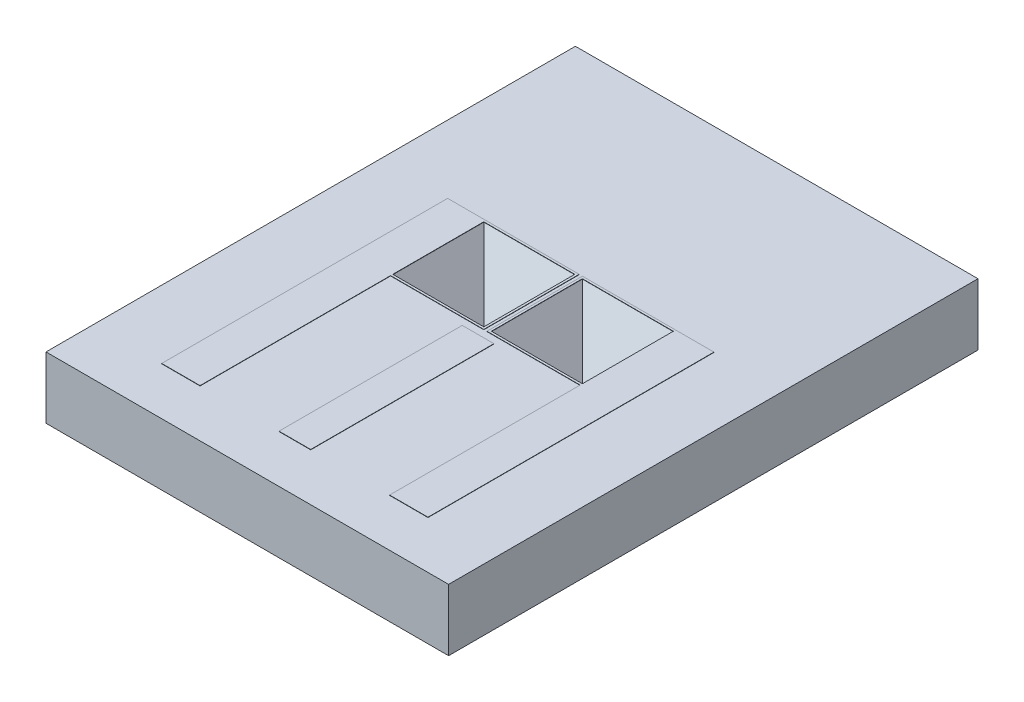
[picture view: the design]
ISO-10303-21;
HEADER;
FILE_DESCRIPTION(('STEP AP214'),'2;1');
FILE_NAME('part.step','',(''),(''),'','','');
FILE_SCHEMA(('AUTOMOTIVE_DESIGN { 1 0 10303 214 1 1 1 1 }'));
ENDSEC;
DATA;
#1=APPLICATION_CONTEXT('core data for automotive mechanical design processes');
#2=APPLICATION_PROTOCOL_DEFINITION('international standard','automotive_design',2000,#1);
#3=PRODUCT_CONTEXT('',#1,'mechanical');
#4=PRODUCT('Part','Part','',(#3));
#5=PRODUCT_RELATED_PRODUCT_CATEGORY('part','',(#4));
#6=PRODUCT_DEFINITION_FORMATION('','',#4);
#7=PRODUCT_DEFINITION_CONTEXT('part definition',#1,'design');
#8=PRODUCT_DEFINITION('design','',#6,#7);
#9=PRODUCT_DEFINITION_SHAPE('','',#8);
#10=(LENGTH_UNIT() NAMED_UNIT(*) SI_UNIT(.MILLI.,.METRE.));
#11=(NAMED_UNIT(*) PLANE_ANGLE_UNIT() SI_UNIT($,.RADIAN.));
#12=(NAMED_UNIT(*) SI_UNIT($,.STERADIAN.) SOLID_ANGLE_UNIT());
#13=UNCERTAINTY_MEASURE_WITH_UNIT(LENGTH_MEASURE(1.E-05),#10,'distance_accuracy_value','');
#14=(GEOMETRIC_REPRESENTATION_CONTEXT(3) GLOBAL_UNCERTAINTY_ASSIGNED_CONTEXT((#13)) GLOBAL_UNIT_ASSIGNED_CONTEXT((#10,
#11,#12)) REPRESENTATION_CONTEXT('',''));
#15=CARTESIAN_POINT('',(0.,0.,0.));
#16=DIRECTION('',(0.,0.,1.));
#17=DIRECTION('',(1.,0.,0.));
#18=AXIS2_PLACEMENT_3D('',#15,#16,#17);
#19=CARTESIAN_POINT('',(-1.6129,-0.4953,4.2418));
#20=DIRECTION('',(0.,1.,0.));
#21=DIRECTION('',(0.,0.,1.));
#22=AXIS2_PLACEMENT_3D('',#19,#20,#21);
#23=PLANE('',#22);
#24=DIRECTION('',(0.,0.,1.));
#25=VECTOR('',#24,1.);
#26=CARTESIAN_POINT('',(-1.6129,-0.4953,0.));
#27=LINE('',#26,#25);
#28=CARTESIAN_POINT('',(-1.6129,-0.4953,0.));
#29=VERTEX_POINT('',#28);
#30=CARTESIAN_POINT('',(-1.6129,-0.4953,4.2418));
#31=VERTEX_POINT('',#30);
#32=EDGE_CURVE('E484',#29,#31,#27,.T.);
#33=ORIENTED_EDGE('',*,*,#32,.F.);
#34=DIRECTION('',(-1.,0.,0.));
#35=VECTOR('',#34,1.);
#36=CARTESIAN_POINT('',(-1.6129,-0.4953,0.));
#37=LINE('',#36,#35);
#38=CARTESIAN_POINT('',(1.6129,-0.4953,0.));
#39=VERTEX_POINT('',#38);
#40=EDGE_CURVE('E494',#39,#29,#37,.T.);
#41=ORIENTED_EDGE('',*,*,#40,.F.);
#42=DIRECTION('',(0.,0.,-1.));
#43=VECTOR('',#42,1.);
#44=CARTESIAN_POINT('',(1.6129,-0.4953,0.));
#45=LINE('',#44,#43);
#46=CARTESIAN_POINT('',(1.6129,-0.4953,4.2418));
#47=VERTEX_POINT('',#46);
#48=EDGE_CURVE('E491',#47,#39,#45,.T.);
#49=ORIENTED_EDGE('',*,*,#48,.F.);
#50=DIRECTION('',(1.,0.,0.));
#51=VECTOR('',#50,1.);
#52=CARTESIAN_POINT('',(-1.6129,-0.4953,4.2418));
#53=LINE('',#52,#51);
#54=EDGE_CURVE('E487',#31,#47,#53,.T.);
#55=ORIENTED_EDGE('',*,*,#54,.F.);
#56=EDGE_LOOP('',(#33,#41,#49,#55));
#57=FACE_BOUND('',#56,.T.);
#58=CARTESIAN_POINT('',(0.,-0.4953,2.1209));
#59=DIRECTION('',(0.,1.,0.));
#60=DIRECTION('',(0.,0.,1.));
#61=AXIS2_PLACEMENT_3D('',#58,#59,#60);
#62=CIRCLE('',#61,0.79375);
#63=CARTESIAN_POINT('',(0.,-0.4953,2.91465));
#64=VERTEX_POINT('',#63);
#65=EDGE_CURVE('E11',#64,#64,#62,.F.);
#66=ORIENTED_EDGE('',*,*,#65,.F.);
#67=EDGE_LOOP('',(#66));
#68=FACE_BOUND('',#67,.T.);
#69=ADVANCED_FACE('F34',(#57,#68),#23,.F.);
#70=CARTESIAN_POINT('',(-1.6129,0.,4.2418));
#71=DIRECTION('',(0.,1.,0.));
#72=DIRECTION('',(0.,0.,1.));
#73=AXIS2_PLACEMENT_3D('',#70,#71,#72);
#74=PLANE('',#73);
#75=DIRECTION('',(0.,0.,1.));
#76=VECTOR('',#75,1.);
#77=CARTESIAN_POINT('',(0.127,0.,2.39268));
#78=LINE('',#77,#76);
#79=CARTESIAN_POINT('',(0.127,0.,2.39268));
#80=VERTEX_POINT('',#79);
#81=CARTESIAN_POINT('',(0.127,0.,3.8608));
#82=VERTEX_POINT('',#81);
#83=EDGE_CURVE('E267',#80,#82,#78,.T.);
#84=ORIENTED_EDGE('',*,*,#83,.T.);
#85=DIRECTION('',(1.,0.,0.));
#86=VECTOR('',#85,1.);
#87=CARTESIAN_POINT('',(0.,0.,3.8608));
#88=LINE('',#87,#86);
#89=CARTESIAN_POINT('',(-0.127,0.,3.8608));
#90=VERTEX_POINT('',#89);
#91=EDGE_CURVE('E257',#90,#82,#88,.T.);
#92=ORIENTED_EDGE('',*,*,#91,.F.);
#93=DIRECTION('',(0.,0.,1.));
#94=VECTOR('',#93,1.);
#95=CARTESIAN_POINT('',(-0.127,0.,2.39268));
#96=LINE('',#95,#94);
#97=CARTESIAN_POINT('',(-0.127,0.,2.39268));
#98=VERTEX_POINT('',#97);
#99=EDGE_CURVE('E376',#98,#90,#96,.T.);
#100=ORIENTED_EDGE('',*,*,#99,.F.);
#101=DIRECTION('',(-1.,0.,0.));
#102=VECTOR('',#101,1.);
#103=CARTESIAN_POINT('',(0.,0.,2.39268));
#104=LINE('',#103,#102);
#105=EDGE_CURVE('E357',#80,#98,#104,.T.);
#106=ORIENTED_EDGE('',*,*,#105,.F.);
#107=EDGE_LOOP('',(#84,#92,#100,#106));
#108=FACE_BOUND('',#107,.T.);
#109=DIRECTION('',(0.,0.,1.));
#110=VECTOR('',#109,1.);
#111=CARTESIAN_POINT('',(1.0668,0.,3.8608));
#112=LINE('',#111,#110);
#113=CARTESIAN_POINT('',(1.0668,0.,1.56972));
#114=VERTEX_POINT('',#113);
#115=CARTESIAN_POINT('',(1.0668,0.,3.8608));
#116=VERTEX_POINT('',#115);
#117=EDGE_CURVE('E297',#114,#116,#112,.T.);
#118=ORIENTED_EDGE('',*,*,#117,.T.);
#119=DIRECTION('',(-1.,0.,0.));
#120=VECTOR('',#119,1.);
#121=CARTESIAN_POINT('',(1.0668,0.,3.8608));
#122=LINE('',#121,#120);
#123=CARTESIAN_POINT('',(0.75946,0.,3.8608));
#124=VERTEX_POINT('',#123);
#125=EDGE_CURVE('E302',#116,#124,#122,.T.);
#126=ORIENTED_EDGE('',*,*,#125,.T.);
#127=DIRECTION('',(0.,0.,-1.));
#128=VECTOR('',#127,1.);
#129=CARTESIAN_POINT('',(0.759459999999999,0.,3.8608));
#130=LINE('',#129,#128);
#131=CARTESIAN_POINT('',(0.759459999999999,0.,2.33426));
#132=VERTEX_POINT('',#131);
#133=EDGE_CURVE('E323',#124,#132,#130,.T.);
#134=ORIENTED_EDGE('',*,*,#133,.T.);
#135=DIRECTION('',(-1.,0.,0.));
#136=VECTOR('',#135,1.);
#137=CARTESIAN_POINT('',(0.759459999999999,0.,2.33426));
#138=LINE('',#137,#136);
#139=CARTESIAN_POINT('',(0.0126999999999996,0.,2.33426));
#140=VERTEX_POINT('',#139);
#141=EDGE_CURVE('E321',#132,#140,#138,.T.);
#142=ORIENTED_EDGE('',*,*,#141,.T.);
#143=DIRECTION('',(0.,0.,-1.));
#144=VECTOR('',#143,1.);
#145=CARTESIAN_POINT('',(0.0126999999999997,0.,2.33426));
#146=LINE('',#145,#144);
#147=CARTESIAN_POINT('',(0.0126999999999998,0.,1.56972));
#148=VERTEX_POINT('',#147);
#149=EDGE_CURVE('E54',#140,#148,#146,.T.);
#150=ORIENTED_EDGE('',*,*,#149,.T.);
#151=DIRECTION('',(1.,0.,0.));
#152=VECTOR('',#151,1.);
#153=CARTESIAN_POINT('',(1.0668,0.,1.56972));
#154=LINE('',#153,#152);
#155=EDGE_CURVE('E49',#148,#114,#154,.T.);
#156=ORIENTED_EDGE('',*,*,#155,.T.);
#157=EDGE_LOOP('',(#118,#126,#134,#142,#150,#156));
#158=FACE_BOUND('',#157,.T.);
#159=DIRECTION('',(0.,0.,1.));
#160=VECTOR('',#159,1.);
#161=CARTESIAN_POINT('',(-1.6129,0.,0.));
#162=LINE('',#161,#160);
#163=CARTESIAN_POINT('',(-1.6129,0.,0.));
#164=VERTEX_POINT('',#163);
#165=CARTESIAN_POINT('',(-1.6129,0.,4.2418));
#166=VERTEX_POINT('',#165);
#167=EDGE_CURVE('E463',#164,#166,#162,.T.);
#168=ORIENTED_EDGE('',*,*,#167,.T.);
#169=DIRECTION('',(1.,0.,0.));
#170=VECTOR('',#169,1.);
#171=CARTESIAN_POINT('',(-1.6129,0.,4.2418));
#172=LINE('',#171,#170);
#173=CARTESIAN_POINT('',(1.6129,0.,4.2418));
#174=VERTEX_POINT('',#173);
#175=EDGE_CURVE('E500',#166,#174,#172,.T.);
#176=ORIENTED_EDGE('',*,*,#175,.T.);
#177=DIRECTION('',(0.,0.,-1.));
#178=VECTOR('',#177,1.);
#179=CARTESIAN_POINT('',(1.6129,0.,0.));
#180=LINE('',#179,#178);
#181=CARTESIAN_POINT('',(1.6129,0.,0.));
#182=VERTEX_POINT('',#181);
#183=EDGE_CURVE('E503',#174,#182,#180,.T.);
#184=ORIENTED_EDGE('',*,*,#183,.T.);
#185=DIRECTION('',(-1.,0.,0.));
#186=VECTOR('',#185,1.);
#187=CARTESIAN_POINT('',(-1.6129,0.,0.));
#188=LINE('',#187,#186);
#189=EDGE_CURVE('E488',#182,#164,#188,.T.);
#190=ORIENTED_EDGE('',*,*,#189,.T.);
#191=EDGE_LOOP('',(#168,#176,#184,#190));
#192=FACE_BOUND('',#191,.T.);
#193=DIRECTION('',(1.,0.,0.));
#194=VECTOR('',#193,1.);
#195=CARTESIAN_POINT('',(-1.0668,0.,3.8608));
#196=LINE('',#195,#194);
#197=CARTESIAN_POINT('',(-1.0668,0.,3.8608));
#198=VERTEX_POINT('',#197);
#199=CARTESIAN_POINT('',(-0.759459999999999,0.,3.8608));
#200=VERTEX_POINT('',#199);
#201=EDGE_CURVE('E422',#198,#200,#196,.T.);
#202=ORIENTED_EDGE('',*,*,#201,.F.);
#203=DIRECTION('',(0.,0.,1.));
#204=VECTOR('',#203,1.);
#205=CARTESIAN_POINT('',(-1.0668,0.,3.8608));
#206=LINE('',#205,#204);
#207=CARTESIAN_POINT('',(-1.0668,0.,1.56972));
#208=VERTEX_POINT('',#207);
#209=EDGE_CURVE('E404',#208,#198,#206,.T.);
#210=ORIENTED_EDGE('',*,*,#209,.F.);
#211=DIRECTION('',(-1.,0.,0.));
#212=VECTOR('',#211,1.);
#213=CARTESIAN_POINT('',(-1.0668,0.,1.56972));
#214=LINE('',#213,#212);
#215=CARTESIAN_POINT('',(-0.0126999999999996,0.,1.56972));
#216=VERTEX_POINT('',#215);
#217=EDGE_CURVE('E409',#216,#208,#214,.T.);
#218=ORIENTED_EDGE('',*,*,#217,.F.);
#219=DIRECTION('',(0.,0.,-1.));
#220=VECTOR('',#219,1.);
#221=CARTESIAN_POINT('',(-0.0126999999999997,0.,2.33426));
#222=LINE('',#221,#220);
#223=CARTESIAN_POINT('',(-0.0126999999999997,0.,2.33426));
#224=VERTEX_POINT('',#223);
#225=EDGE_CURVE('E428',#224,#216,#222,.T.);
#226=ORIENTED_EDGE('',*,*,#225,.F.);
#227=DIRECTION('',(1.,0.,0.));
#228=VECTOR('',#227,1.);
#229=CARTESIAN_POINT('',(-0.759459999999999,0.,2.33426));
#230=LINE('',#229,#228);
#231=CARTESIAN_POINT('',(-0.759459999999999,0.,2.33426));
#232=VERTEX_POINT('',#231);
#233=EDGE_CURVE('E426',#232,#224,#230,.T.);
#234=ORIENTED_EDGE('',*,*,#233,.F.);
#235=DIRECTION('',(0.,0.,-1.));
#236=VECTOR('',#235,1.);
#237=CARTESIAN_POINT('',(-0.759459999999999,0.,3.8608));
#238=LINE('',#237,#236);
#239=EDGE_CURVE('E424',#200,#232,#238,.T.);
#240=ORIENTED_EDGE('',*,*,#239,.F.);
#241=EDGE_LOOP('',(#202,#210,#218,#226,#234,#240));
#242=FACE_BOUND('',#241,.T.);
#243=ADVANCED_FACE('F521',(#108,#158,#192,#242),#74,.T.);
#244=CARTESIAN_POINT('',(-1.6129,-0.4953,0.));
#245=DIRECTION('',(-1.,0.,0.));
#246=DIRECTION('',(0.,0.,1.));
#247=AXIS2_PLACEMENT_3D('',#244,#245,#246);
#248=PLANE('',#247);
#249=ORIENTED_EDGE('',*,*,#167,.F.);
#250=DIRECTION('',(0.,1.,0.));
#251=VECTOR('',#250,1.);
#252=CARTESIAN_POINT('',(-1.6129,-0.4953,0.));
#253=LINE('',#252,#251);
#254=EDGE_CURVE('E42',#29,#164,#253,.T.);
#255=ORIENTED_EDGE('',*,*,#254,.F.);
#256=ORIENTED_EDGE('',*,*,#32,.T.);
#257=DIRECTION('',(0.,1.,0.));
#258=VECTOR('',#257,1.);
#259=CARTESIAN_POINT('',(-1.6129,-0.4953,4.2418));
#260=LINE('',#259,#258);
#261=EDGE_CURVE('E497',#31,#166,#260,.T.);
#262=ORIENTED_EDGE('',*,*,#261,.T.);
#263=EDGE_LOOP('',(#249,#255,#256,#262));
#264=FACE_BOUND('',#263,.T.);
#265=ADVANCED_FACE('F36',(#264),#248,.T.);
#266=CARTESIAN_POINT('',(-1.6129,-0.4953,0.));
#267=DIRECTION('',(0.,0.,-1.));
#268=DIRECTION('',(-1.,0.,0.));
#269=AXIS2_PLACEMENT_3D('',#266,#267,#268);
#270=PLANE('',#269);
#271=ORIENTED_EDGE('',*,*,#189,.F.);
#272=DIRECTION('',(0.,1.,0.));
#273=VECTOR('',#272,1.);
#274=CARTESIAN_POINT('',(1.6129,-0.4953,0.));
#275=LINE('',#274,#273);
#276=EDGE_CURVE('E509',#39,#182,#275,.T.);
#277=ORIENTED_EDGE('',*,*,#276,.F.);
#278=ORIENTED_EDGE('',*,*,#40,.T.);
#279=ORIENTED_EDGE('',*,*,#254,.T.);
#280=EDGE_LOOP('',(#271,#277,#278,#279));
#281=FACE_BOUND('',#280,.T.);
#282=ADVANCED_FACE('F525',(#281),#270,.T.);
#283=CARTESIAN_POINT('',(1.6129,-0.4953,0.));
#284=DIRECTION('',(1.,0.,0.));
#285=DIRECTION('',(0.,0.,-1.));
#286=AXIS2_PLACEMENT_3D('',#283,#284,#285);
#287=PLANE('',#286);
#288=ORIENTED_EDGE('',*,*,#183,.F.);
#289=DIRECTION('',(0.,1.,0.));
#290=VECTOR('',#289,1.);
#291=CARTESIAN_POINT('',(1.6129,-0.4953,4.2418));
#292=LINE('',#291,#290);
#293=EDGE_CURVE('E511',#47,#174,#292,.T.);
#294=ORIENTED_EDGE('',*,*,#293,.F.);
#295=ORIENTED_EDGE('',*,*,#48,.T.);
#296=ORIENTED_EDGE('',*,*,#276,.T.);
#297=EDGE_LOOP('',(#288,#294,#295,#296));
#298=FACE_BOUND('',#297,.T.);
#299=ADVANCED_FACE('F531',(#298),#287,.T.);
#300=CARTESIAN_POINT('',(-1.6129,-0.4953,4.2418));
#301=DIRECTION('',(0.,0.,1.));
#302=DIRECTION('',(1.,0.,0.));
#303=AXIS2_PLACEMENT_3D('',#300,#301,#302);
#304=PLANE('',#303);
#305=ORIENTED_EDGE('',*,*,#175,.F.);
#306=ORIENTED_EDGE('',*,*,#261,.F.);
#307=ORIENTED_EDGE('',*,*,#54,.T.);
#308=ORIENTED_EDGE('',*,*,#293,.T.);
#309=EDGE_LOOP('',(#305,#306,#307,#308));
#310=FACE_BOUND('',#309,.T.);
#311=ADVANCED_FACE('F518',(#310),#304,.T.);
#312=CARTESIAN_POINT('',(-1.0668,0.00254,1.56972));
#313=DIRECTION('',(0.,-1.,0.));
#314=DIRECTION('',(0.,0.,-1.));
#315=AXIS2_PLACEMENT_3D('',#312,#313,#314);
#316=PLANE('',#315);
#317=DIRECTION('',(0.,0.,1.));
#318=VECTOR('',#317,1.);
#319=CARTESIAN_POINT('',(-1.0668,0.00254,3.8608));
#320=LINE('',#319,#318);
#321=CARTESIAN_POINT('',(-1.0668,0.00254,1.56972));
#322=VERTEX_POINT('',#321);
#323=CARTESIAN_POINT('',(-1.0668,0.00254,3.8608));
#324=VERTEX_POINT('',#323);
#325=EDGE_CURVE('E405',#322,#324,#320,.T.);
#326=ORIENTED_EDGE('',*,*,#325,.T.);
#327=DIRECTION('',(1.,0.,0.));
#328=VECTOR('',#327,1.);
#329=CARTESIAN_POINT('',(-1.0668,0.00254,3.8608));
#330=LINE('',#329,#328);
#331=CARTESIAN_POINT('',(-0.759459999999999,0.00254,3.8608));
#332=VERTEX_POINT('',#331);
#333=EDGE_CURVE('E408',#324,#332,#330,.T.);
#334=ORIENTED_EDGE('',*,*,#333,.T.);
#335=DIRECTION('',(0.,0.,-1.));
#336=VECTOR('',#335,1.);
#337=CARTESIAN_POINT('',(-0.759459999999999,0.00254,3.8608));
#338=LINE('',#337,#336);
#339=CARTESIAN_POINT('',(-0.759459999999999,0.00254,2.33426));
#340=VERTEX_POINT('',#339);
#341=EDGE_CURVE('E411',#332,#340,#338,.T.);
#342=ORIENTED_EDGE('',*,*,#341,.T.);
#343=DIRECTION('',(1.,0.,0.));
#344=VECTOR('',#343,1.);
#345=CARTESIAN_POINT('',(-0.759459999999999,0.00254,2.33426));
#346=LINE('',#345,#344);
#347=CARTESIAN_POINT('',(-0.0126999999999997,0.00254,2.33426));
#348=VERTEX_POINT('',#347);
#349=EDGE_CURVE('E413',#340,#348,#346,.T.);
#350=ORIENTED_EDGE('',*,*,#349,.T.);
#351=DIRECTION('',(0.,0.,-1.));
#352=VECTOR('',#351,1.);
#353=CARTESIAN_POINT('',(-0.0126999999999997,0.00254,2.33426));
#354=LINE('',#353,#352);
#355=CARTESIAN_POINT('',(-0.0126999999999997,0.00254,1.56972));
#356=VERTEX_POINT('',#355);
#357=EDGE_CURVE('E415',#348,#356,#354,.T.);
#358=ORIENTED_EDGE('',*,*,#357,.T.);
#359=DIRECTION('',(-1.,0.,0.));
#360=VECTOR('',#359,1.);
#361=CARTESIAN_POINT('',(-1.0668,0.00254,1.56972));
#362=LINE('',#361,#360);
#363=EDGE_CURVE('E417',#356,#322,#362,.T.);
#364=ORIENTED_EDGE('',*,*,#363,.T.);
#365=EDGE_LOOP('',(#326,#334,#342,#350,#358,#364));
#366=FACE_BOUND('',#365,.T.);
#367=DIRECTION('',(0.,0.,1.));
#368=VECTOR('',#367,1.);
#369=CARTESIAN_POINT('',(-0.75946,0.00254,1.5875));
#370=LINE('',#369,#368);
#371=CARTESIAN_POINT('',(-0.75946,0.00254,1.5875));
#372=VERTEX_POINT('',#371);
#373=CARTESIAN_POINT('',(-0.75946,0.00254,2.31648));
#374=VERTEX_POINT('',#373);
#375=EDGE_CURVE('E384',#372,#374,#370,.T.);
#376=ORIENTED_EDGE('',*,*,#375,.F.);
#377=DIRECTION('',(-1.,0.,0.));
#378=VECTOR('',#377,1.);
#379=CARTESIAN_POINT('',(-0.0304799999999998,0.00254,1.5875));
#380=LINE('',#379,#378);
#381=CARTESIAN_POINT('',(-0.0304799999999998,0.00254,1.5875));
#382=VERTEX_POINT('',#381);
#383=EDGE_CURVE('E391',#382,#372,#380,.T.);
#384=ORIENTED_EDGE('',*,*,#383,.F.);
#385=DIRECTION('',(0.,0.,-1.));
#386=VECTOR('',#385,1.);
#387=CARTESIAN_POINT('',(-0.0304799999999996,0.00254,2.31648));
#388=LINE('',#387,#386);
#389=CARTESIAN_POINT('',(-0.0304799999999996,0.00254,2.31648));
#390=VERTEX_POINT('',#389);
#391=EDGE_CURVE('E388',#390,#382,#388,.T.);
#392=ORIENTED_EDGE('',*,*,#391,.F.);
#393=DIRECTION('',(1.,0.,0.));
#394=VECTOR('',#393,1.);
#395=CARTESIAN_POINT('',(-0.75946,0.00254,2.31648));
#396=LINE('',#395,#394);
#397=EDGE_CURVE('E386',#374,#390,#396,.T.);
#398=ORIENTED_EDGE('',*,*,#397,.F.);
#399=EDGE_LOOP('',(#376,#384,#392,#398));
#400=FACE_BOUND('',#399,.T.);
#401=ADVANCED_FACE('F538',(#366,#400),#316,.F.);
#402=CARTESIAN_POINT('',(-1.0668,0.00254,3.8608));
#403=DIRECTION('',(1.,0.,0.));
#404=DIRECTION('',(0.,0.,-1.));
#405=AXIS2_PLACEMENT_3D('',#402,#403,#404);
#406=PLANE('',#405);
#407=ORIENTED_EDGE('',*,*,#209,.T.);
#408=DIRECTION('',(0.,-1.,0.));
#409=VECTOR('',#408,1.);
#410=CARTESIAN_POINT('',(-1.0668,0.00254,3.8608));
#411=LINE('',#410,#409);
#412=EDGE_CURVE('E445',#324,#198,#411,.T.);
#413=ORIENTED_EDGE('',*,*,#412,.F.);
#414=ORIENTED_EDGE('',*,*,#325,.F.);
#415=DIRECTION('',(0.,-1.,0.));
#416=VECTOR('',#415,1.);
#417=CARTESIAN_POINT('',(-1.0668,0.00254,1.56972));
#418=LINE('',#417,#416);
#419=EDGE_CURVE('E419',#322,#208,#418,.T.);
#420=ORIENTED_EDGE('',*,*,#419,.T.);
#421=EDGE_LOOP('',(#407,#413,#414,#420));
#422=FACE_BOUND('',#421,.T.);
#423=ADVANCED_FACE('F570',(#422),#406,.F.);
#424=CARTESIAN_POINT('',(-1.0668,0.00254,3.8608));
#425=DIRECTION('',(0.,0.,-1.));
#426=DIRECTION('',(-1.,0.,0.));
#427=AXIS2_PLACEMENT_3D('',#424,#425,#426);
#428=PLANE('',#427);
#429=ORIENTED_EDGE('',*,*,#201,.T.);
#430=DIRECTION('',(0.,-1.,0.));
#431=VECTOR('',#430,1.);
#432=CARTESIAN_POINT('',(-0.759459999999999,0.00254,3.8608));
#433=LINE('',#432,#431);
#434=EDGE_CURVE('E442',#332,#200,#433,.T.);
#435=ORIENTED_EDGE('',*,*,#434,.F.);
#436=ORIENTED_EDGE('',*,*,#333,.F.);
#437=ORIENTED_EDGE('',*,*,#412,.T.);
#438=EDGE_LOOP('',(#429,#435,#436,#437));
#439=FACE_BOUND('',#438,.T.);
#440=ADVANCED_FACE('F573',(#439),#428,.F.);
#441=CARTESIAN_POINT('',(-0.759459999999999,0.00254,3.8608));
#442=DIRECTION('',(-1.,0.,0.));
#443=DIRECTION('',(0.,0.,1.));
#444=AXIS2_PLACEMENT_3D('',#441,#442,#443);
#445=PLANE('',#444);
#446=ORIENTED_EDGE('',*,*,#239,.T.);
#447=DIRECTION('',(0.,-1.,0.));
#448=VECTOR('',#447,1.);
#449=CARTESIAN_POINT('',(-0.759459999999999,0.00254,2.33426));
#450=LINE('',#449,#448);
#451=EDGE_CURVE('E439',#340,#232,#450,.T.);
#452=ORIENTED_EDGE('',*,*,#451,.F.);
#453=ORIENTED_EDGE('',*,*,#341,.F.);
#454=ORIENTED_EDGE('',*,*,#434,.T.);
#455=EDGE_LOOP('',(#446,#452,#453,#454));
#456=FACE_BOUND('',#455,.T.);
#457=ADVANCED_FACE('F577',(#456),#445,.F.);
#458=CARTESIAN_POINT('',(-0.759459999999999,0.00254,2.33426));
#459=DIRECTION('',(0.,0.,-1.));
#460=DIRECTION('',(-1.,0.,0.));
#461=AXIS2_PLACEMENT_3D('',#458,#459,#460);
#462=PLANE('',#461);
#463=ORIENTED_EDGE('',*,*,#233,.T.);
#464=DIRECTION('',(0.,-1.,0.));
#465=VECTOR('',#464,1.);
#466=CARTESIAN_POINT('',(-0.0126999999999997,0.00254,2.33426));
#467=LINE('',#466,#465);
#468=EDGE_CURVE('E436',#348,#224,#467,.T.);
#469=ORIENTED_EDGE('',*,*,#468,.F.);
#470=ORIENTED_EDGE('',*,*,#349,.F.);
#471=ORIENTED_EDGE('',*,*,#451,.T.);
#472=EDGE_LOOP('',(#463,#469,#470,#471));
#473=FACE_BOUND('',#472,.T.);
#474=ADVANCED_FACE('F581',(#473),#462,.F.);
#475=CARTESIAN_POINT('',(-0.0126999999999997,0.00254,2.33426));
#476=DIRECTION('',(-1.,0.,0.));
#477=DIRECTION('',(0.,0.,1.));
#478=AXIS2_PLACEMENT_3D('',#475,#476,#477);
#479=PLANE('',#478);
#480=ORIENTED_EDGE('',*,*,#225,.T.);
#481=DIRECTION('',(0.,-1.,0.));
#482=VECTOR('',#481,1.);
#483=CARTESIAN_POINT('',(-0.0126999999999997,0.00254,1.56972));
#484=LINE('',#483,#482);
#485=EDGE_CURVE('E434',#356,#216,#484,.T.);
#486=ORIENTED_EDGE('',*,*,#485,.F.);
#487=ORIENTED_EDGE('',*,*,#357,.F.);
#488=ORIENTED_EDGE('',*,*,#468,.T.);
#489=EDGE_LOOP('',(#480,#486,#487,#488));
#490=FACE_BOUND('',#489,.T.);
#491=ADVANCED_FACE('F585',(#490),#479,.F.);
#492=CARTESIAN_POINT('',(-1.0668,0.00254,1.56972));
#493=DIRECTION('',(0.,0.,1.));
#494=DIRECTION('',(1.,0.,0.));
#495=AXIS2_PLACEMENT_3D('',#492,#493,#494);
#496=PLANE('',#495);
#497=ORIENTED_EDGE('',*,*,#217,.T.);
#498=ORIENTED_EDGE('',*,*,#419,.F.);
#499=ORIENTED_EDGE('',*,*,#363,.F.);
#500=ORIENTED_EDGE('',*,*,#485,.T.);
#501=EDGE_LOOP('',(#497,#498,#499,#500));
#502=FACE_BOUND('',#501,.T.);
#503=ADVANCED_FACE('F589',(#502),#496,.F.);
#504=CARTESIAN_POINT('',(-0.75946,0.00254,1.5875));
#505=DIRECTION('',(1.,0.,0.));
#506=DIRECTION('',(0.,0.,-1.));
#507=AXIS2_PLACEMENT_3D('',#504,#505,#506);
#508=PLANE('',#507);
#509=DIRECTION('',(0.,0.,1.));
#510=VECTOR('',#509,1.);
#511=CARTESIAN_POINT('',(-0.75946,0.,1.5875));
#512=LINE('',#511,#510);
#513=CARTESIAN_POINT('',(-0.75946,0.,1.5875));
#514=VERTEX_POINT('',#513);
#515=CARTESIAN_POINT('',(-0.75946,0.,2.31648));
#516=VERTEX_POINT('',#515);
#517=EDGE_CURVE('E447',#514,#516,#512,.T.);
#518=ORIENTED_EDGE('',*,*,#517,.F.);
#519=DIRECTION('',(0.,-1.,0.));
#520=VECTOR('',#519,1.);
#521=CARTESIAN_POINT('',(-0.75946,0.00254,1.5875));
#522=LINE('',#521,#520);
#523=EDGE_CURVE('E393',#372,#514,#522,.T.);
#524=ORIENTED_EDGE('',*,*,#523,.F.);
#525=ORIENTED_EDGE('',*,*,#375,.T.);
#526=DIRECTION('',(0.,-1.,0.));
#527=VECTOR('',#526,1.);
#528=CARTESIAN_POINT('',(-0.75946,0.00254,2.31648));
#529=LINE('',#528,#527);
#530=EDGE_CURVE('E401',#374,#516,#529,.T.);
#531=ORIENTED_EDGE('',*,*,#530,.T.);
#532=EDGE_LOOP('',(#518,#524,#525,#531));
#533=FACE_BOUND('',#532,.T.);
#534=ADVANCED_FACE('F593',(#533),#508,.T.);
#535=CARTESIAN_POINT('',(-0.75946,0.00254,2.31648));
#536=DIRECTION('',(0.,0.,-1.));
#537=DIRECTION('',(-1.,0.,0.));
#538=AXIS2_PLACEMENT_3D('',#535,#536,#537);
#539=PLANE('',#538);
#540=DIRECTION('',(1.,0.,0.));
#541=VECTOR('',#540,1.);
#542=CARTESIAN_POINT('',(-0.75946,0.,2.31648));
#543=LINE('',#542,#541);
#544=CARTESIAN_POINT('',(-0.0304799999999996,0.,2.31648));
#545=VERTEX_POINT('',#544);
#546=EDGE_CURVE('E450',#516,#545,#543,.T.);
#547=ORIENTED_EDGE('',*,*,#546,.F.);
#548=ORIENTED_EDGE('',*,*,#530,.F.);
#549=ORIENTED_EDGE('',*,*,#397,.T.);
#550=DIRECTION('',(0.,-1.,0.));
#551=VECTOR('',#550,1.);
#552=CARTESIAN_POINT('',(-0.0304799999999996,0.00254,2.31648));
#553=LINE('',#552,#551);
#554=EDGE_CURVE('E398',#390,#545,#553,.T.);
#555=ORIENTED_EDGE('',*,*,#554,.T.);
#556=EDGE_LOOP('',(#547,#548,#549,#555));
#557=FACE_BOUND('',#556,.T.);
#558=ADVANCED_FACE('F600',(#557),#539,.T.);
#559=CARTESIAN_POINT('',(-0.0304799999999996,0.00254,2.31648));
#560=DIRECTION('',(-1.,0.,0.));
#561=DIRECTION('',(0.,0.,1.));
#562=AXIS2_PLACEMENT_3D('',#559,#560,#561);
#563=PLANE('',#562);
#564=DIRECTION('',(0.,0.,-1.));
#565=VECTOR('',#564,1.);
#566=CARTESIAN_POINT('',(-0.0304799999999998,0.,1.5875));
#567=LINE('',#566,#565);
#568=CARTESIAN_POINT('',(-0.0304799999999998,0.,1.5875));
#569=VERTEX_POINT('',#568);
#570=EDGE_CURVE('E453',#545,#569,#567,.T.);
#571=ORIENTED_EDGE('',*,*,#570,.F.);
#572=ORIENTED_EDGE('',*,*,#554,.F.);
#573=ORIENTED_EDGE('',*,*,#391,.T.);
#574=DIRECTION('',(0.,-1.,0.));
#575=VECTOR('',#574,1.);
#576=CARTESIAN_POINT('',(-0.0304799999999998,0.00254,1.5875));
#577=LINE('',#576,#575);
#578=EDGE_CURVE('E396',#382,#569,#577,.T.);
#579=ORIENTED_EDGE('',*,*,#578,.T.);
#580=EDGE_LOOP('',(#571,#572,#573,#579));
#581=FACE_BOUND('',#580,.T.);
#582=ADVANCED_FACE('F604',(#581),#563,.T.);
#583=CARTESIAN_POINT('',(-0.0304799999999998,0.00254,1.5875));
#584=DIRECTION('',(0.,0.,1.));
#585=DIRECTION('',(1.,0.,0.));
#586=AXIS2_PLACEMENT_3D('',#583,#584,#585);
#587=PLANE('',#586);
#588=DIRECTION('',(-1.,0.,0.));
#589=VECTOR('',#588,1.);
#590=CARTESIAN_POINT('',(-0.75946,0.,1.5875));
#591=LINE('',#590,#589);
#592=EDGE_CURVE('E456',#569,#514,#591,.T.);
#593=ORIENTED_EDGE('',*,*,#592,.F.);
#594=ORIENTED_EDGE('',*,*,#578,.F.);
#595=ORIENTED_EDGE('',*,*,#383,.T.);
#596=ORIENTED_EDGE('',*,*,#523,.T.);
#597=EDGE_LOOP('',(#593,#594,#595,#596));
#598=FACE_BOUND('',#597,.T.);
#599=ADVANCED_FACE('F568',(#598),#587,.T.);
#600=CARTESIAN_POINT('',(-0.75946,-0.4826,2.31648));
#601=DIRECTION('',(0.,1.,0.));
#602=DIRECTION('',(0.,0.,1.));
#603=AXIS2_PLACEMENT_3D('',#600,#601,#602);
#604=PLANE('',#603);
#605=DIRECTION('',(0.,0.,1.));
#606=VECTOR('',#605,1.);
#607=CARTESIAN_POINT('',(-0.457898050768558,-0.4826,2.31648));
#608=LINE('',#607,#606);
#609=CARTESIAN_POINT('',(-0.457898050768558,-0.4826,1.88906194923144));
#610=VERTEX_POINT('',#609);
#611=CARTESIAN_POINT('',(-0.457898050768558,-0.4826,2.01491805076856));
#612=VERTEX_POINT('',#611);
#613=EDGE_CURVE('E459',#610,#612,#608,.T.);
#614=ORIENTED_EDGE('',*,*,#613,.T.);
#615=DIRECTION('',(1.,0.,0.));
#616=VECTOR('',#615,1.);
#617=CARTESIAN_POINT('',(-0.75946,-0.4826,2.01491805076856));
#618=LINE('',#617,#616);
#619=CARTESIAN_POINT('',(-0.332041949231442,-0.4826,2.01491805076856));
#620=VERTEX_POINT('',#619);
#621=EDGE_CURVE('E476',#612,#620,#618,.T.);
#622=ORIENTED_EDGE('',*,*,#621,.T.);
#623=DIRECTION('',(0.,0.,-1.));
#624=VECTOR('',#623,1.);
#625=CARTESIAN_POINT('',(-0.332041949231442,-0.4826,2.31648));
#626=LINE('',#625,#624);
#627=CARTESIAN_POINT('',(-0.332041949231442,-0.4826,1.88906194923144));
#628=VERTEX_POINT('',#627);
#629=EDGE_CURVE('E479',#620,#628,#626,.T.);
#630=ORIENTED_EDGE('',*,*,#629,.T.);
#631=DIRECTION('',(-1.,0.,0.));
#632=VECTOR('',#631,1.);
#633=CARTESIAN_POINT('',(-0.75946,-0.4826,1.88906194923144));
#634=LINE('',#633,#632);
#635=EDGE_CURVE('E469',#628,#610,#634,.T.);
#636=ORIENTED_EDGE('',*,*,#635,.T.);
#637=EDGE_LOOP('',(#614,#622,#630,#636));
#638=FACE_BOUND('',#637,.T.);
#639=ADVANCED_FACE('F560',(#638),#604,.T.);
#640=CARTESIAN_POINT('',(-0.75946,0.,2.31648));
#641=DIRECTION('',(0.,-0.529919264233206,0.848048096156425));
#642=DIRECTION('',(0.,-0.848048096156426,-0.529919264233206));
#643=AXIS2_PLACEMENT_3D('',#640,#641,#642);
#644=PLANE('',#643);
#645=ORIENTED_EDGE('',*,*,#546,.T.);
#646=DIRECTION('',(0.468237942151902,0.749337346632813,0.468237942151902));
#647=VECTOR('',#646,1.);
#648=CARTESIAN_POINT('',(-0.190306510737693,-0.25577588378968,2.15665348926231));
#649=LINE('',#648,#647);
#650=EDGE_CURVE('E468',#620,#545,#649,.T.);
#651=ORIENTED_EDGE('',*,*,#650,.F.);
#652=ORIENTED_EDGE('',*,*,#621,.F.);
#653=DIRECTION('',(-0.468237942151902,0.749337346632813,0.468237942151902));
#654=VECTOR('',#653,1.);
#655=CARTESIAN_POINT('',(-0.599633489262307,-0.25577588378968,2.15665348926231));
#656=LINE('',#655,#654);
#657=EDGE_CURVE('E465',#612,#516,#656,.T.);
#658=ORIENTED_EDGE('',*,*,#657,.T.);
#659=EDGE_LOOP('',(#645,#651,#652,#658));
#660=FACE_BOUND('',#659,.T.);
#661=ADVANCED_FACE('F556',(#660),#644,.F.);
#662=CARTESIAN_POINT('',(-0.0304799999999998,0.,1.5875));
#663=DIRECTION('',(0.848048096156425,-0.529919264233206,0.));
#664=DIRECTION('',(0.529919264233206,0.848048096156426,0.));
#665=AXIS2_PLACEMENT_3D('',#662,#663,#664);
#666=PLANE('',#665);
#667=ORIENTED_EDGE('',*,*,#570,.T.);
#668=DIRECTION('',(0.468237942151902,0.749337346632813,-0.468237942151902));
#669=VECTOR('',#668,1.);
#670=CARTESIAN_POINT('',(-0.0304799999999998,0.,1.5875));
#671=LINE('',#670,#669);
#672=EDGE_CURVE('E464',#628,#569,#671,.T.);
#673=ORIENTED_EDGE('',*,*,#672,.F.);
#674=ORIENTED_EDGE('',*,*,#629,.F.);
#675=ORIENTED_EDGE('',*,*,#650,.T.);
#676=EDGE_LOOP('',(#667,#673,#674,#675));
#677=FACE_BOUND('',#676,.T.);
#678=ADVANCED_FACE('F552',(#677),#666,.F.);
#679=CARTESIAN_POINT('',(-0.75946,0.,1.5875));
#680=DIRECTION('',(0.,-0.529919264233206,-0.848048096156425));
#681=DIRECTION('',(0.,0.848048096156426,-0.529919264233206));
#682=AXIS2_PLACEMENT_3D('',#679,#680,#681);
#683=PLANE('',#682);
#684=ORIENTED_EDGE('',*,*,#592,.T.);
#685=DIRECTION('',(-0.468237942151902,0.749337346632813,-0.468237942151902));
#686=VECTOR('',#685,1.);
#687=CARTESIAN_POINT('',(-0.75946,0.,1.5875));
#688=LINE('',#687,#686);
#689=EDGE_CURVE('E460',#610,#514,#688,.T.);
#690=ORIENTED_EDGE('',*,*,#689,.F.);
#691=ORIENTED_EDGE('',*,*,#635,.F.);
#692=ORIENTED_EDGE('',*,*,#672,.T.);
#693=EDGE_LOOP('',(#684,#690,#691,#692));
#694=FACE_BOUND('',#693,.T.);
#695=ADVANCED_FACE('F548',(#694),#683,.F.);
#696=CARTESIAN_POINT('',(-0.75946,0.,1.5875));
#697=DIRECTION('',(-0.848048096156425,-0.529919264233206,0.));
#698=DIRECTION('',(0.529919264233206,-0.848048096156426,0.));
#699=AXIS2_PLACEMENT_3D('',#696,#697,#698);
#700=PLANE('',#699);
#701=ORIENTED_EDGE('',*,*,#517,.T.);
#702=ORIENTED_EDGE('',*,*,#657,.F.);
#703=ORIENTED_EDGE('',*,*,#613,.F.);
#704=ORIENTED_EDGE('',*,*,#689,.T.);
#705=EDGE_LOOP('',(#701,#702,#703,#704));
#706=FACE_BOUND('',#705,.T.);
#707=ADVANCED_FACE('F551',(#706),#700,.F.);
#708=CARTESIAN_POINT('',(0.,0.00254,2.39268));
#709=DIRECTION('',(0.,0.,1.));
#710=DIRECTION('',(1.,0.,0.));
#711=AXIS2_PLACEMENT_3D('',#708,#709,#710);
#712=PLANE('',#711);
#713=ORIENTED_EDGE('',*,*,#105,.T.);
#714=DIRECTION('',(0.,-1.,0.));
#715=VECTOR('',#714,1.);
#716=CARTESIAN_POINT('',(-0.127,0.00254,2.39268));
#717=LINE('',#716,#715);
#718=CARTESIAN_POINT('',(-0.127,0.00254,2.39268));
#719=VERTEX_POINT('',#718);
#720=EDGE_CURVE('E381',#719,#98,#717,.T.);
#721=ORIENTED_EDGE('',*,*,#720,.F.);
#722=DIRECTION('',(-1.,0.,0.));
#723=VECTOR('',#722,1.);
#724=CARTESIAN_POINT('',(0.,0.00254,2.39268));
#725=LINE('',#724,#723);
#726=CARTESIAN_POINT('',(0.127,0.00254,2.39268));
#727=VERTEX_POINT('',#726);
#728=EDGE_CURVE('E372',#727,#719,#725,.T.);
#729=ORIENTED_EDGE('',*,*,#728,.F.);
#730=DIRECTION('',(0.,-1.,0.));
#731=VECTOR('',#730,1.);
#732=CARTESIAN_POINT('',(0.127,0.00254,2.39268));
#733=LINE('',#732,#731);
#734=EDGE_CURVE('E262',#727,#80,#733,.T.);
#735=ORIENTED_EDGE('',*,*,#734,.T.);
#736=EDGE_LOOP('',(#713,#721,#729,#735));
#737=FACE_BOUND('',#736,.T.);
#738=ADVANCED_FACE('F564',(#737),#712,.F.);
#739=CARTESIAN_POINT('',(-0.127,0.00254,2.39268));
#740=DIRECTION('',(1.,0.,0.));
#741=DIRECTION('',(0.,0.,-1.));
#742=AXIS2_PLACEMENT_3D('',#739,#740,#741);
#743=PLANE('',#742);
#744=ORIENTED_EDGE('',*,*,#99,.T.);
#745=DIRECTION('',(0.,-1.,0.));
#746=VECTOR('',#745,1.);
#747=CARTESIAN_POINT('',(-0.127,0.00254,3.8608));
#748=LINE('',#747,#746);
#749=CARTESIAN_POINT('',(-0.127,0.00254,3.8608));
#750=VERTEX_POINT('',#749);
#751=EDGE_CURVE('E251',#750,#90,#748,.T.);
#752=ORIENTED_EDGE('',*,*,#751,.F.);
#753=DIRECTION('',(0.,0.,1.));
#754=VECTOR('',#753,1.);
#755=CARTESIAN_POINT('',(-0.127,0.00254,2.39268));
#756=LINE('',#755,#754);
#757=EDGE_CURVE('E248',#719,#750,#756,.T.);
#758=ORIENTED_EDGE('',*,*,#757,.F.);
#759=ORIENTED_EDGE('',*,*,#720,.T.);
#760=EDGE_LOOP('',(#744,#752,#758,#759));
#761=FACE_BOUND('',#760,.T.);
#762=ADVANCED_FACE('F614',(#761),#743,.F.);
#763=CARTESIAN_POINT('',(0.,0.00254,3.8608));
#764=DIRECTION('',(0.,0.,-1.));
#765=DIRECTION('',(-1.,0.,0.));
#766=AXIS2_PLACEMENT_3D('',#763,#764,#765);
#767=PLANE('',#766);
#768=ORIENTED_EDGE('',*,*,#91,.T.);
#769=DIRECTION('',(0.,-1.,0.));
#770=VECTOR('',#769,1.);
#771=CARTESIAN_POINT('',(0.127,0.00254,3.8608));
#772=LINE('',#771,#770);
#773=CARTESIAN_POINT('',(0.127,0.00254,3.8608));
#774=VERTEX_POINT('',#773);
#775=EDGE_CURVE('E254',#774,#82,#772,.T.);
#776=ORIENTED_EDGE('',*,*,#775,.F.);
#777=DIRECTION('',(1.,0.,0.));
#778=VECTOR('',#777,1.);
#779=CARTESIAN_POINT('',(0.,0.00254,3.8608));
#780=LINE('',#779,#778);
#781=EDGE_CURVE('E242',#750,#774,#780,.T.);
#782=ORIENTED_EDGE('',*,*,#781,.F.);
#783=ORIENTED_EDGE('',*,*,#751,.T.);
#784=EDGE_LOOP('',(#768,#776,#782,#783));
#785=FACE_BOUND('',#784,.T.);
#786=ADVANCED_FACE('F255',(#785),#767,.F.);
#787=CARTESIAN_POINT('',(0.,0.00254,3.8608));
#788=DIRECTION('',(0.,-1.,0.));
#789=DIRECTION('',(0.,0.,-1.));
#790=AXIS2_PLACEMENT_3D('',#787,#788,#789);
#791=PLANE('',#790);
#792=ORIENTED_EDGE('',*,*,#781,.T.);
#793=DIRECTION('',(0.,0.,1.));
#794=VECTOR('',#793,1.);
#795=CARTESIAN_POINT('',(0.127,0.00254,2.39268));
#796=LINE('',#795,#794);
#797=EDGE_CURVE('E246',#727,#774,#796,.T.);
#798=ORIENTED_EDGE('',*,*,#797,.F.);
#799=ORIENTED_EDGE('',*,*,#728,.T.);
#800=ORIENTED_EDGE('',*,*,#757,.T.);
#801=EDGE_LOOP('',(#792,#798,#799,#800));
#802=FACE_BOUND('',#801,.T.);
#803=ADVANCED_FACE('F244',(#802),#791,.F.);
#804=CARTESIAN_POINT('',(1.0668,0.00254,3.8608));
#805=DIRECTION('',(1.,0.,0.));
#806=DIRECTION('',(0.,0.,-1.));
#807=AXIS2_PLACEMENT_3D('',#804,#805,#806);
#808=PLANE('',#807);
#809=ORIENTED_EDGE('',*,*,#117,.F.);
#810=DIRECTION('',(0.,-1.,0.));
#811=VECTOR('',#810,1.);
#812=CARTESIAN_POINT('',(1.0668,0.00254,1.56972));
#813=LINE('',#812,#811);
#814=CARTESIAN_POINT('',(1.0668,0.00254,1.56972));
#815=VERTEX_POINT('',#814);
#816=EDGE_CURVE('E339',#815,#114,#813,.T.);
#817=ORIENTED_EDGE('',*,*,#816,.F.);
#818=DIRECTION('',(0.,0.,1.));
#819=VECTOR('',#818,1.);
#820=CARTESIAN_POINT('',(1.0668,0.00254,3.8608));
#821=LINE('',#820,#819);
#822=CARTESIAN_POINT('',(1.0668,0.00254,3.8608));
#823=VERTEX_POINT('',#822);
#824=EDGE_CURVE('E298',#815,#823,#821,.T.);
#825=ORIENTED_EDGE('',*,*,#824,.T.);
#826=DIRECTION('',(0.,-1.,0.));
#827=VECTOR('',#826,1.);
#828=CARTESIAN_POINT('',(1.0668,0.00254,3.8608));
#829=LINE('',#828,#827);
#830=EDGE_CURVE('E317',#823,#116,#829,.T.);
#831=ORIENTED_EDGE('',*,*,#830,.T.);
#832=EDGE_LOOP('',(#809,#817,#825,#831));
#833=FACE_BOUND('',#832,.T.);
#834=ADVANCED_FACE('F623',(#833),#808,.T.);
#835=CARTESIAN_POINT('',(1.0668,0.00254,1.56972));
#836=DIRECTION('',(0.,0.,-1.));
#837=DIRECTION('',(-1.,0.,0.));
#838=AXIS2_PLACEMENT_3D('',#835,#836,#837);
#839=PLANE('',#838);
#840=ORIENTED_EDGE('',*,*,#155,.F.);
#841=DIRECTION('',(0.,-1.,0.));
#842=VECTOR('',#841,1.);
#843=CARTESIAN_POINT('',(0.0126999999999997,0.00254,1.56972));
#844=LINE('',#843,#842);
#845=CARTESIAN_POINT('',(0.0126999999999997,0.00254,1.56972));
#846=VERTEX_POINT('',#845);
#847=EDGE_CURVE('E337',#846,#148,#844,.T.);
#848=ORIENTED_EDGE('',*,*,#847,.F.);
#849=DIRECTION('',(1.,0.,0.));
#850=VECTOR('',#849,1.);
#851=CARTESIAN_POINT('',(1.0668,0.00254,1.56972));
#852=LINE('',#851,#850);
#853=EDGE_CURVE('E301',#846,#815,#852,.T.);
#854=ORIENTED_EDGE('',*,*,#853,.T.);
#855=ORIENTED_EDGE('',*,*,#816,.T.);
#856=EDGE_LOOP('',(#840,#848,#854,#855));
#857=FACE_BOUND('',#856,.T.);
#858=ADVANCED_FACE('F647',(#857),#839,.T.);
#859=CARTESIAN_POINT('',(0.0126999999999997,0.00254,2.33426));
#860=DIRECTION('',(-1.,0.,0.));
#861=DIRECTION('',(0.,0.,1.));
#862=AXIS2_PLACEMENT_3D('',#859,#860,#861);
#863=PLANE('',#862);
#864=ORIENTED_EDGE('',*,*,#149,.F.);
#865=DIRECTION('',(0.,-1.,0.));
#866=VECTOR('',#865,1.);
#867=CARTESIAN_POINT('',(0.0126999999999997,0.00254,2.33426));
#868=LINE('',#867,#866);
#869=CARTESIAN_POINT('',(0.0126999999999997,0.00254,2.33426));
#870=VERTEX_POINT('',#869);
#871=EDGE_CURVE('E334',#870,#140,#868,.T.);
#872=ORIENTED_EDGE('',*,*,#871,.F.);
#873=DIRECTION('',(0.,0.,-1.));
#874=VECTOR('',#873,1.);
#875=CARTESIAN_POINT('',(0.0126999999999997,0.00254,2.33426));
#876=LINE('',#875,#874);
#877=EDGE_CURVE('E305',#870,#846,#876,.T.);
#878=ORIENTED_EDGE('',*,*,#877,.T.);
#879=ORIENTED_EDGE('',*,*,#847,.T.);
#880=EDGE_LOOP('',(#864,#872,#878,#879));
#881=FACE_BOUND('',#880,.T.);
#882=ADVANCED_FACE('F651',(#881),#863,.T.);
#883=CARTESIAN_POINT('',(0.759459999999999,0.00254,2.33426));
#884=DIRECTION('',(0.,0.,1.));
#885=DIRECTION('',(1.,0.,0.));
#886=AXIS2_PLACEMENT_3D('',#883,#884,#885);
#887=PLANE('',#886);
#888=ORIENTED_EDGE('',*,*,#141,.F.);
#889=DIRECTION('',(0.,-1.,0.));
#890=VECTOR('',#889,1.);
#891=CARTESIAN_POINT('',(0.759459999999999,0.00254,2.33426));
#892=LINE('',#891,#890);
#893=CARTESIAN_POINT('',(0.759459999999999,0.00254,2.33426));
#894=VERTEX_POINT('',#893);
#895=EDGE_CURVE('E331',#894,#132,#892,.T.);
#896=ORIENTED_EDGE('',*,*,#895,.F.);
#897=DIRECTION('',(-1.,0.,0.));
#898=VECTOR('',#897,1.);
#899=CARTESIAN_POINT('',(0.759459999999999,0.00254,2.33426));
#900=LINE('',#899,#898);
#901=EDGE_CURVE('E308',#894,#870,#900,.T.);
#902=ORIENTED_EDGE('',*,*,#901,.T.);
#903=ORIENTED_EDGE('',*,*,#871,.T.);
#904=EDGE_LOOP('',(#888,#896,#902,#903));
#905=FACE_BOUND('',#904,.T.);
#906=ADVANCED_FACE('F655',(#905),#887,.T.);
#907=CARTESIAN_POINT('',(0.759459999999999,0.00254,3.8608));
#908=DIRECTION('',(-1.,0.,0.));
#909=DIRECTION('',(0.,0.,1.));
#910=AXIS2_PLACEMENT_3D('',#907,#908,#909);
#911=PLANE('',#910);
#912=ORIENTED_EDGE('',*,*,#133,.F.);
#913=DIRECTION('',(0.,-1.,0.));
#914=VECTOR('',#913,1.);
#915=CARTESIAN_POINT('',(0.759459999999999,0.00254,3.8608));
#916=LINE('',#915,#914);
#917=CARTESIAN_POINT('',(0.759459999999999,0.00254,3.8608));
#918=VERTEX_POINT('',#917);
#919=EDGE_CURVE('E328',#918,#124,#916,.T.);
#920=ORIENTED_EDGE('',*,*,#919,.F.);
#921=DIRECTION('',(0.,0.,-1.));
#922=VECTOR('',#921,1.);
#923=CARTESIAN_POINT('',(0.759459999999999,0.00254,3.8608));
#924=LINE('',#923,#922);
#925=EDGE_CURVE('E311',#918,#894,#924,.T.);
#926=ORIENTED_EDGE('',*,*,#925,.T.);
#927=ORIENTED_EDGE('',*,*,#895,.T.);
#928=EDGE_LOOP('',(#912,#920,#926,#927));
#929=FACE_BOUND('',#928,.T.);
#930=ADVANCED_FACE('F659',(#929),#911,.T.);
#931=CARTESIAN_POINT('',(1.0668,0.00254,3.8608));
#932=DIRECTION('',(0.,0.,1.));
#933=DIRECTION('',(1.,0.,0.));
#934=AXIS2_PLACEMENT_3D('',#931,#932,#933);
#935=PLANE('',#934);
#936=ORIENTED_EDGE('',*,*,#125,.F.);
#937=ORIENTED_EDGE('',*,*,#830,.F.);
#938=DIRECTION('',(-1.,0.,0.));
#939=VECTOR('',#938,1.);
#940=CARTESIAN_POINT('',(1.0668,0.00254,3.8608));
#941=LINE('',#940,#939);
#942=EDGE_CURVE('E314',#823,#918,#941,.T.);
#943=ORIENTED_EDGE('',*,*,#942,.T.);
#944=ORIENTED_EDGE('',*,*,#919,.T.);
#945=EDGE_LOOP('',(#936,#937,#943,#944));
#946=FACE_BOUND('',#945,.T.);
#947=ADVANCED_FACE('F663',(#946),#935,.T.);
#948=CARTESIAN_POINT('',(1.0668,0.00254,1.56972));
#949=DIRECTION('',(0.,-1.,0.));
#950=DIRECTION('',(0.,0.,-1.));
#951=AXIS2_PLACEMENT_3D('',#948,#949,#950);
#952=PLANE('',#951);
#953=DIRECTION('',(1.,0.,0.));
#954=VECTOR('',#953,1.);
#955=CARTESIAN_POINT('',(0.0304799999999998,0.00254,1.5875));
#956=LINE('',#955,#954);
#957=CARTESIAN_POINT('',(0.0304799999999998,0.00254,1.5875));
#958=VERTEX_POINT('',#957);
#959=CARTESIAN_POINT('',(0.75946,0.00254,1.5875));
#960=VERTEX_POINT('',#959);
#961=EDGE_CURVE('E276',#958,#960,#956,.T.);
#962=ORIENTED_EDGE('',*,*,#961,.T.);
#963=DIRECTION('',(0.,0.,1.));
#964=VECTOR('',#963,1.);
#965=CARTESIAN_POINT('',(0.75946,0.00254,1.5875));
#966=LINE('',#965,#964);
#967=CARTESIAN_POINT('',(0.75946,0.00254,2.31648));
#968=VERTEX_POINT('',#967);
#969=EDGE_CURVE('E261',#960,#968,#966,.T.);
#970=ORIENTED_EDGE('',*,*,#969,.T.);
#971=DIRECTION('',(-1.,0.,0.));
#972=VECTOR('',#971,1.);
#973=CARTESIAN_POINT('',(0.75946,0.00254,2.31648));
#974=LINE('',#973,#972);
#975=CARTESIAN_POINT('',(0.0304799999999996,0.00254,2.31648));
#976=VERTEX_POINT('',#975);
#977=EDGE_CURVE('E282',#968,#976,#974,.T.);
#978=ORIENTED_EDGE('',*,*,#977,.T.);
#979=DIRECTION('',(0.,0.,-1.));
#980=VECTOR('',#979,1.);
#981=CARTESIAN_POINT('',(0.0304799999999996,0.00254,2.31648));
#982=LINE('',#981,#980);
#983=EDGE_CURVE('E279',#976,#958,#982,.T.);
#984=ORIENTED_EDGE('',*,*,#983,.T.);
#985=EDGE_LOOP('',(#962,#970,#978,#984));
#986=FACE_BOUND('',#985,.T.);
#987=ORIENTED_EDGE('',*,*,#824,.F.);
#988=ORIENTED_EDGE('',*,*,#853,.F.);
#989=ORIENTED_EDGE('',*,*,#877,.F.);
#990=ORIENTED_EDGE('',*,*,#901,.F.);
#991=ORIENTED_EDGE('',*,*,#925,.F.);
#992=ORIENTED_EDGE('',*,*,#942,.F.);
#993=EDGE_LOOP('',(#987,#988,#989,#990,#991,#992));
#994=FACE_BOUND('',#993,.T.);
#995=ADVANCED_FACE('F667',(#986,#994),#952,.F.);
#996=CARTESIAN_POINT('',(0.75946,0.00254,1.5875));
#997=DIRECTION('',(1.,0.,0.));
#998=DIRECTION('',(0.,0.,-1.));
#999=AXIS2_PLACEMENT_3D('',#996,#997,#998);
#1000=PLANE('',#999);
#1001=DIRECTION('',(0.,0.,1.));
#1002=VECTOR('',#1001,1.);
#1003=CARTESIAN_POINT('',(0.75946,0.,1.5875));
#1004=LINE('',#1003,#1002);
#1005=CARTESIAN_POINT('',(0.75946,0.,1.5875));
#1006=VERTEX_POINT('',#1005);
#1007=CARTESIAN_POINT('',(0.75946,0.,2.31648));
#1008=VERTEX_POINT('',#1007);
#1009=EDGE_CURVE('E341',#1006,#1008,#1004,.T.);
#1010=ORIENTED_EDGE('',*,*,#1009,.T.);
#1011=DIRECTION('',(0.,-1.,0.));
#1012=VECTOR('',#1011,1.);
#1013=CARTESIAN_POINT('',(0.75946,0.00254,2.31648));
#1014=LINE('',#1013,#1012);
#1015=EDGE_CURVE('E285',#968,#1008,#1014,.T.);
#1016=ORIENTED_EDGE('',*,*,#1015,.F.);
#1017=ORIENTED_EDGE('',*,*,#969,.F.);
#1018=DIRECTION('',(0.,-1.,0.));
#1019=VECTOR('',#1018,1.);
#1020=CARTESIAN_POINT('',(0.75946,0.00254,1.5875));
#1021=LINE('',#1020,#1019);
#1022=EDGE_CURVE('E294',#960,#1006,#1021,.T.);
#1023=ORIENTED_EDGE('',*,*,#1022,.T.);
#1024=EDGE_LOOP('',(#1010,#1016,#1017,#1023));
#1025=FACE_BOUND('',#1024,.T.);
#1026=ADVANCED_FACE('F671',(#1025),#1000,.F.);
#1027=CARTESIAN_POINT('',(0.0304799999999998,0.00254,1.5875));
#1028=DIRECTION('',(0.,0.,-1.));
#1029=DIRECTION('',(-1.,0.,0.));
#1030=AXIS2_PLACEMENT_3D('',#1027,#1028,#1029);
#1031=PLANE('',#1030);
#1032=DIRECTION('',(1.,0.,0.));
#1033=VECTOR('',#1032,1.);
#1034=CARTESIAN_POINT('',(0.75946,0.,1.5875));
#1035=LINE('',#1034,#1033);
#1036=CARTESIAN_POINT('',(0.0304799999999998,0.,1.5875));
#1037=VERTEX_POINT('',#1036);
#1038=EDGE_CURVE('E344',#1037,#1006,#1035,.T.);
#1039=ORIENTED_EDGE('',*,*,#1038,.T.);
#1040=ORIENTED_EDGE('',*,*,#1022,.F.);
#1041=ORIENTED_EDGE('',*,*,#961,.F.);
#1042=DIRECTION('',(0.,-1.,0.));
#1043=VECTOR('',#1042,1.);
#1044=CARTESIAN_POINT('',(0.0304799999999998,0.00254,1.5875));
#1045=LINE('',#1044,#1043);
#1046=EDGE_CURVE('E291',#958,#1037,#1045,.T.);
#1047=ORIENTED_EDGE('',*,*,#1046,.T.);
#1048=EDGE_LOOP('',(#1039,#1040,#1041,#1047));
#1049=FACE_BOUND('',#1048,.T.);
#1050=ADVANCED_FACE('F675',(#1049),#1031,.F.);
#1051=CARTESIAN_POINT('',(0.0304799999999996,0.00254,2.31648));
#1052=DIRECTION('',(-1.,0.,0.));
#1053=DIRECTION('',(0.,0.,1.));
#1054=AXIS2_PLACEMENT_3D('',#1051,#1052,#1053);
#1055=PLANE('',#1054);
#1056=DIRECTION('',(0.,0.,-1.));
#1057=VECTOR('',#1056,1.);
#1058=CARTESIAN_POINT('',(0.0304799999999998,0.,1.5875));
#1059=LINE('',#1058,#1057);
#1060=CARTESIAN_POINT('',(0.0304799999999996,0.,2.31648));
#1061=VERTEX_POINT('',#1060);
#1062=EDGE_CURVE('E347',#1061,#1037,#1059,.T.);
#1063=ORIENTED_EDGE('',*,*,#1062,.T.);
#1064=ORIENTED_EDGE('',*,*,#1046,.F.);
#1065=ORIENTED_EDGE('',*,*,#983,.F.);
#1066=DIRECTION('',(0.,-1.,0.));
#1067=VECTOR('',#1066,1.);
#1068=CARTESIAN_POINT('',(0.0304799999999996,0.00254,2.31648));
#1069=LINE('',#1068,#1067);
#1070=EDGE_CURVE('E288',#976,#1061,#1069,.T.);
#1071=ORIENTED_EDGE('',*,*,#1070,.T.);
#1072=EDGE_LOOP('',(#1063,#1064,#1065,#1071));
#1073=FACE_BOUND('',#1072,.T.);
#1074=ADVANCED_FACE('F679',(#1073),#1055,.F.);
#1075=CARTESIAN_POINT('',(0.75946,0.00254,2.31648));
#1076=DIRECTION('',(0.,0.,1.));
#1077=DIRECTION('',(1.,0.,0.));
#1078=AXIS2_PLACEMENT_3D('',#1075,#1076,#1077);
#1079=PLANE('',#1078);
#1080=DIRECTION('',(-1.,0.,0.));
#1081=VECTOR('',#1080,1.);
#1082=CARTESIAN_POINT('',(0.75946,0.,2.31648));
#1083=LINE('',#1082,#1081);
#1084=EDGE_CURVE('E350',#1008,#1061,#1083,.T.);
#1085=ORIENTED_EDGE('',*,*,#1084,.T.);
#1086=ORIENTED_EDGE('',*,*,#1070,.F.);
#1087=ORIENTED_EDGE('',*,*,#977,.F.);
#1088=ORIENTED_EDGE('',*,*,#1015,.T.);
#1089=EDGE_LOOP('',(#1085,#1086,#1087,#1088));
#1090=FACE_BOUND('',#1089,.T.);
#1091=ADVANCED_FACE('F643',(#1090),#1079,.F.);
#1092=CARTESIAN_POINT('',(0.75946,-0.4826,2.31648));
#1093=DIRECTION('',(0.,1.,0.));
#1094=DIRECTION('',(0.,0.,1.));
#1095=AXIS2_PLACEMENT_3D('',#1092,#1093,#1094);
#1096=PLANE('',#1095);
#1097=DIRECTION('',(0.,0.,-1.));
#1098=VECTOR('',#1097,1.);
#1099=CARTESIAN_POINT('',(0.457898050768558,-0.4826,2.31648));
#1100=LINE('',#1099,#1098);
#1101=CARTESIAN_POINT('',(0.457898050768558,-0.4826,1.88906194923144));
#1102=VERTEX_POINT('',#1101);
#1103=CARTESIAN_POINT('',(0.457898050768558,-0.4826,2.01491805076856));
#1104=VERTEX_POINT('',#1103);
#1105=EDGE_CURVE('E353',#1102,#1104,#1100,.F.);
#1106=ORIENTED_EDGE('',*,*,#1105,.F.);
#1107=DIRECTION('',(-1.,0.,0.));
#1108=VECTOR('',#1107,1.);
#1109=CARTESIAN_POINT('',(0.75946,-0.4826,1.88906194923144));
#1110=LINE('',#1109,#1108);
#1111=CARTESIAN_POINT('',(0.332041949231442,-0.4826,1.88906194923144));
#1112=VERTEX_POINT('',#1111);
#1113=EDGE_CURVE('E367',#1112,#1102,#1110,.F.);
#1114=ORIENTED_EDGE('',*,*,#1113,.F.);
#1115=DIRECTION('',(0.,0.,1.));
#1116=VECTOR('',#1115,1.);
#1117=CARTESIAN_POINT('',(0.332041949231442,-0.4826,2.31648));
#1118=LINE('',#1117,#1116);
#1119=CARTESIAN_POINT('',(0.332041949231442,-0.4826,2.01491805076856));
#1120=VERTEX_POINT('',#1119);
#1121=EDGE_CURVE('E369',#1120,#1112,#1118,.F.);
#1122=ORIENTED_EDGE('',*,*,#1121,.F.);
#1123=DIRECTION('',(1.,0.,0.));
#1124=VECTOR('',#1123,1.);
#1125=CARTESIAN_POINT('',(0.75946,-0.4826,2.01491805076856));
#1126=LINE('',#1125,#1124);
#1127=EDGE_CURVE('E362',#1104,#1120,#1126,.F.);
#1128=ORIENTED_EDGE('',*,*,#1127,.F.);
#1129=EDGE_LOOP('',(#1106,#1114,#1122,#1128));
#1130=FACE_BOUND('',#1129,.T.);
#1131=ADVANCED_FACE('F636',(#1130),#1096,.T.);
#1132=CARTESIAN_POINT('',(0.75946,0.,1.5875));
#1133=DIRECTION('',(0.,-0.529919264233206,-0.848048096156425));
#1134=DIRECTION('',(0.,0.848048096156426,-0.529919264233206));
#1135=AXIS2_PLACEMENT_3D('',#1132,#1133,#1134);
#1136=PLANE('',#1135);
#1137=ORIENTED_EDGE('',*,*,#1038,.F.);
#1138=DIRECTION('',(-0.468237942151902,0.749337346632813,-0.468237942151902));
#1139=VECTOR('',#1138,1.);
#1140=CARTESIAN_POINT('',(0.190306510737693,-0.255775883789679,1.74732651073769));
#1141=LINE('',#1140,#1139);
#1142=EDGE_CURVE('E361',#1112,#1037,#1141,.T.);
#1143=ORIENTED_EDGE('',*,*,#1142,.F.);
#1144=ORIENTED_EDGE('',*,*,#1113,.T.);
#1145=DIRECTION('',(0.468237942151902,0.749337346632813,-0.468237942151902));
#1146=VECTOR('',#1145,1.);
#1147=CARTESIAN_POINT('',(0.75946,0.,1.5875));
#1148=LINE('',#1147,#1146);
#1149=EDGE_CURVE('E359',#1102,#1006,#1148,.T.);
#1150=ORIENTED_EDGE('',*,*,#1149,.T.);
#1151=EDGE_LOOP('',(#1137,#1143,#1144,#1150));
#1152=FACE_BOUND('',#1151,.T.);
#1153=ADVANCED_FACE('F632',(#1152),#1136,.F.);
#1154=CARTESIAN_POINT('',(0.0304799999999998,0.,1.5875));
#1155=DIRECTION('',(-0.848048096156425,-0.529919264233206,0.));
#1156=DIRECTION('',(0.529919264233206,-0.848048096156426,0.));
#1157=AXIS2_PLACEMENT_3D('',#1154,#1155,#1156);
#1158=PLANE('',#1157);
#1159=ORIENTED_EDGE('',*,*,#1062,.F.);
#1160=DIRECTION('',(-0.468237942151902,0.749337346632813,0.468237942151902));
#1161=VECTOR('',#1160,1.);
#1162=CARTESIAN_POINT('',(0.190306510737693,-0.25577588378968,2.15665348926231));
#1163=LINE('',#1162,#1161);
#1164=EDGE_CURVE('E358',#1120,#1061,#1163,.T.);
#1165=ORIENTED_EDGE('',*,*,#1164,.F.);
#1166=ORIENTED_EDGE('',*,*,#1121,.T.);
#1167=ORIENTED_EDGE('',*,*,#1142,.T.);
#1168=EDGE_LOOP('',(#1159,#1165,#1166,#1167));
#1169=FACE_BOUND('',#1168,.T.);
#1170=ADVANCED_FACE('F628',(#1169),#1158,.F.);
#1171=CARTESIAN_POINT('',(0.75946,0.,2.31648));
#1172=DIRECTION('',(0.,-0.529919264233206,0.848048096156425));
#1173=DIRECTION('',(0.,-0.848048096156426,-0.529919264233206));
#1174=AXIS2_PLACEMENT_3D('',#1171,#1172,#1173);
#1175=PLANE('',#1174);
#1176=ORIENTED_EDGE('',*,*,#1084,.F.);
#1177=DIRECTION('',(0.468237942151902,0.749337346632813,0.468237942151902));
#1178=VECTOR('',#1177,1.);
#1179=CARTESIAN_POINT('',(0.75946,0.,2.31648));
#1180=LINE('',#1179,#1178);
#1181=EDGE_CURVE('E354',#1104,#1008,#1180,.T.);
#1182=ORIENTED_EDGE('',*,*,#1181,.F.);
#1183=ORIENTED_EDGE('',*,*,#1127,.T.);
#1184=ORIENTED_EDGE('',*,*,#1164,.T.);
#1185=EDGE_LOOP('',(#1176,#1182,#1183,#1184));
#1186=FACE_BOUND('',#1185,.T.);
#1187=ADVANCED_FACE('F624',(#1186),#1175,.F.);
#1188=CARTESIAN_POINT('',(0.75946,0.,1.5875));
#1189=DIRECTION('',(0.848048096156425,-0.529919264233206,0.));
#1190=DIRECTION('',(0.529919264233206,0.848048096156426,0.));
#1191=AXIS2_PLACEMENT_3D('',#1188,#1189,#1190);
#1192=PLANE('',#1191);
#1193=ORIENTED_EDGE('',*,*,#1009,.F.);
#1194=ORIENTED_EDGE('',*,*,#1149,.F.);
#1195=ORIENTED_EDGE('',*,*,#1105,.T.);
#1196=ORIENTED_EDGE('',*,*,#1181,.T.);
#1197=EDGE_LOOP('',(#1193,#1194,#1195,#1196));
#1198=FACE_BOUND('',#1197,.T.);
#1199=ADVANCED_FACE('F627',(#1198),#1192,.F.);
#1200=CARTESIAN_POINT('',(0.127,0.00254,2.39268));
#1201=DIRECTION('',(1.,0.,0.));
#1202=DIRECTION('',(0.,0.,-1.));
#1203=AXIS2_PLACEMENT_3D('',#1200,#1201,#1202);
#1204=PLANE('',#1203);
#1205=ORIENTED_EDGE('',*,*,#83,.F.);
#1206=ORIENTED_EDGE('',*,*,#734,.F.);
#1207=ORIENTED_EDGE('',*,*,#797,.T.);
#1208=ORIENTED_EDGE('',*,*,#775,.T.);
#1209=EDGE_LOOP('',(#1205,#1206,#1207,#1208));
#1210=FACE_BOUND('',#1209,.T.);
#1211=ADVANCED_FACE('F265',(#1210),#1204,.T.);
#1212=CARTESIAN_POINT('',(0.,-0.5207,2.1209));
#1213=DIRECTION('',(0.,1.,0.));
#1214=DIRECTION('',(0.,0.,1.));
#1215=AXIS2_PLACEMENT_3D('',#1212,#1213,#1214);
#1216=CYLINDRICAL_SURFACE('',#1215,0.79375);
#1217=CARTESIAN_POINT('',(0.,-0.5207,2.1209));
#1218=DIRECTION('',(0.,-1.,0.));
#1219=DIRECTION('',(0.,0.,-1.));
#1220=AXIS2_PLACEMENT_3D('',#1217,#1218,#1219);
#1221=CIRCLE('',#1220,0.79375);
#1222=CARTESIAN_POINT('',(0.,-0.5207,1.32715));
#1223=VERTEX_POINT('',#1222);
#1224=EDGE_CURVE('E270',#1223,#1223,#1221,.T.);
#1225=ORIENTED_EDGE('',*,*,#1224,.F.);
#1226=EDGE_LOOP('',(#1225));
#1227=FACE_BOUND('',#1226,.T.);
#1228=ORIENTED_EDGE('',*,*,#65,.T.);
#1229=EDGE_LOOP('',(#1228));
#1230=FACE_BOUND('',#1229,.T.);
#1231=ADVANCED_FACE('F689',(#1227,#1230),#1216,.T.);
#1232=CARTESIAN_POINT('',(0.,-0.5207,2.1209));
#1233=DIRECTION('',(0.,-1.,0.));
#1234=DIRECTION('',(0.,0.,-1.));
#1235=AXIS2_PLACEMENT_3D('',#1232,#1233,#1234);
#1236=PLANE('',#1235);
#1237=ORIENTED_EDGE('',*,*,#1224,.T.);
#1238=EDGE_LOOP('',(#1237));
#1239=FACE_BOUND('',#1238,.T.);
#1240=ADVANCED_FACE('F692',(#1239),#1236,.T.);
#1241=CLOSED_SHELL('',(#69,#243,#265,#282,#299,#311,#401,#423,#440,#457,#474,#491,#503,#534,
#558,#582,#599,#639,#661,#678,#695,#707,#738,#762,#786,#803,#834,#858,#882,#906,#930,#947,#995,
#1026,#1050,#1074,#1091,#1131,#1153,#1170,#1187,#1199,#1211,#1231,#1240));
#1242=MANIFOLD_SOLID_BREP('B2',#1241);
#1243=ADVANCED_BREP_SHAPE_REPRESENTATION('',(#18,#1242),#14);
#1244=SHAPE_DEFINITION_REPRESENTATION(#9,#1243);
ENDSEC;
END-ISO-10303-21;
